VERSION 5.7 ;
BUSBITCHARS "[]" ;
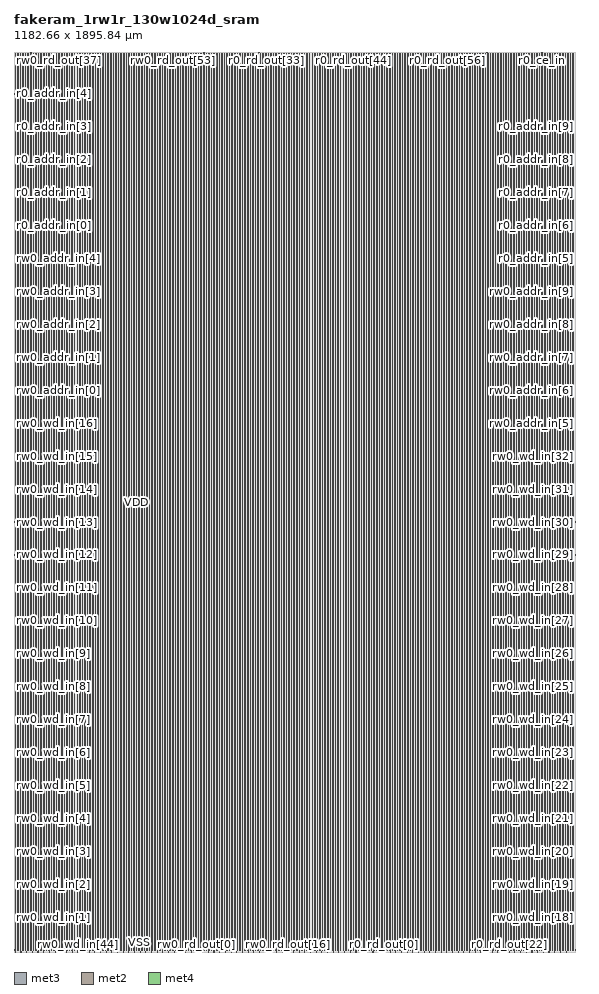
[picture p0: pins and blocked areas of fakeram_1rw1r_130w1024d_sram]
MACRO fakeram_1rw1r_130w1024d_sram
  FOREIGN fakeram_1rw1r_130w1024d_sram 0 0 ;
  SYMMETRY X Y R90 ;
  SIZE 1182.660 BY 1895.840 ;
  CLASS BLOCK ;
  PIN rw0_wd_in[0]
    DIRECTION INPUT ;
    USE SIGNAL ;
    SHAPE ABUTMENT ;
    PORT
      LAYER met3 ;
      RECT 0.000 3.930 0.900 4.230 ;
    END
  END rw0_wd_in[0]
  PIN rw0_wd_in[1]
    DIRECTION INPUT ;
    USE SIGNAL ;
    SHAPE ABUTMENT ;
    PORT
      LAYER met3 ;
      RECT 0.000 73.290 0.900 73.590 ;
    END
  END rw0_wd_in[1]
  PIN rw0_wd_in[2]
    DIRECTION INPUT ;
    USE SIGNAL ;
    SHAPE ABUTMENT ;
    PORT
      LAYER met3 ;
      RECT 0.000 142.650 0.900 142.950 ;
    END
  END rw0_wd_in[2]
  PIN rw0_wd_in[3]
    DIRECTION INPUT ;
    USE SIGNAL ;
    SHAPE ABUTMENT ;
    PORT
      LAYER met3 ;
      RECT 0.000 212.010 0.900 212.310 ;
    END
  END rw0_wd_in[3]
  PIN rw0_wd_in[4]
    DIRECTION INPUT ;
    USE SIGNAL ;
    SHAPE ABUTMENT ;
    PORT
      LAYER met3 ;
      RECT 0.000 281.370 0.900 281.670 ;
    END
  END rw0_wd_in[4]
  PIN rw0_wd_in[5]
    DIRECTION INPUT ;
    USE SIGNAL ;
    SHAPE ABUTMENT ;
    PORT
      LAYER met3 ;
      RECT 0.000 350.730 0.900 351.030 ;
    END
  END rw0_wd_in[5]
  PIN rw0_wd_in[6]
    DIRECTION INPUT ;
    USE SIGNAL ;
    SHAPE ABUTMENT ;
    PORT
      LAYER met3 ;
      RECT 0.000 420.090 0.900 420.390 ;
    END
  END rw0_wd_in[6]
  PIN rw0_wd_in[7]
    DIRECTION INPUT ;
    USE SIGNAL ;
    SHAPE ABUTMENT ;
    PORT
      LAYER met3 ;
      RECT 0.000 489.450 0.900 489.750 ;
    END
  END rw0_wd_in[7]
  PIN rw0_wd_in[8]
    DIRECTION INPUT ;
    USE SIGNAL ;
    SHAPE ABUTMENT ;
    PORT
      LAYER met3 ;
      RECT 0.000 558.810 0.900 559.110 ;
    END
  END rw0_wd_in[8]
  PIN rw0_wd_in[9]
    DIRECTION INPUT ;
    USE SIGNAL ;
    SHAPE ABUTMENT ;
    PORT
      LAYER met3 ;
      RECT 0.000 628.170 0.900 628.470 ;
    END
  END rw0_wd_in[9]
  PIN rw0_wd_in[10]
    DIRECTION INPUT ;
    USE SIGNAL ;
    SHAPE ABUTMENT ;
    PORT
      LAYER met3 ;
      RECT 0.000 697.530 0.900 697.830 ;
    END
  END rw0_wd_in[10]
  PIN rw0_wd_in[11]
    DIRECTION INPUT ;
    USE SIGNAL ;
    SHAPE ABUTMENT ;
    PORT
      LAYER met3 ;
      RECT 0.000 766.890 0.900 767.190 ;
    END
  END rw0_wd_in[11]
  PIN rw0_wd_in[12]
    DIRECTION INPUT ;
    USE SIGNAL ;
    SHAPE ABUTMENT ;
    PORT
      LAYER met3 ;
      RECT 0.000 836.250 0.900 836.550 ;
    END
  END rw0_wd_in[12]
  PIN rw0_wd_in[13]
    DIRECTION INPUT ;
    USE SIGNAL ;
    SHAPE ABUTMENT ;
    PORT
      LAYER met3 ;
      RECT 0.000 905.610 0.900 905.910 ;
    END
  END rw0_wd_in[13]
  PIN rw0_wd_in[14]
    DIRECTION INPUT ;
    USE SIGNAL ;
    SHAPE ABUTMENT ;
    PORT
      LAYER met3 ;
      RECT 0.000 974.970 0.900 975.270 ;
    END
  END rw0_wd_in[14]
  PIN rw0_wd_in[15]
    DIRECTION INPUT ;
    USE SIGNAL ;
    SHAPE ABUTMENT ;
    PORT
      LAYER met3 ;
      RECT 0.000 1044.330 0.900 1044.630 ;
    END
  END rw0_wd_in[15]
  PIN rw0_wd_in[16]
    DIRECTION INPUT ;
    USE SIGNAL ;
    SHAPE ABUTMENT ;
    PORT
      LAYER met3 ;
      RECT 0.000 1113.690 0.900 1113.990 ;
    END
  END rw0_wd_in[16]
  PIN rw0_wd_in[17]
    DIRECTION INPUT ;
    USE SIGNAL ;
    SHAPE ABUTMENT ;
    PORT
      LAYER met3 ;
      RECT 1181.760 3.930 1182.660 4.230 ;
    END
  END rw0_wd_in[17]
  PIN rw0_wd_in[18]
    DIRECTION INPUT ;
    USE SIGNAL ;
    SHAPE ABUTMENT ;
    PORT
      LAYER met3 ;
      RECT 1181.760 73.290 1182.660 73.590 ;
    END
  END rw0_wd_in[18]
  PIN rw0_wd_in[19]
    DIRECTION INPUT ;
    USE SIGNAL ;
    SHAPE ABUTMENT ;
    PORT
      LAYER met3 ;
      RECT 1181.760 142.650 1182.660 142.950 ;
    END
  END rw0_wd_in[19]
  PIN rw0_wd_in[20]
    DIRECTION INPUT ;
    USE SIGNAL ;
    SHAPE ABUTMENT ;
    PORT
      LAYER met3 ;
      RECT 1181.760 212.010 1182.660 212.310 ;
    END
  END rw0_wd_in[20]
  PIN rw0_wd_in[21]
    DIRECTION INPUT ;
    USE SIGNAL ;
    SHAPE ABUTMENT ;
    PORT
      LAYER met3 ;
      RECT 1181.760 281.370 1182.660 281.670 ;
    END
  END rw0_wd_in[21]
  PIN rw0_wd_in[22]
    DIRECTION INPUT ;
    USE SIGNAL ;
    SHAPE ABUTMENT ;
    PORT
      LAYER met3 ;
      RECT 1181.760 350.730 1182.660 351.030 ;
    END
  END rw0_wd_in[22]
  PIN rw0_wd_in[23]
    DIRECTION INPUT ;
    USE SIGNAL ;
    SHAPE ABUTMENT ;
    PORT
      LAYER met3 ;
      RECT 1181.760 420.090 1182.660 420.390 ;
    END
  END rw0_wd_in[23]
  PIN rw0_wd_in[24]
    DIRECTION INPUT ;
    USE SIGNAL ;
    SHAPE ABUTMENT ;
    PORT
      LAYER met3 ;
      RECT 1181.760 489.450 1182.660 489.750 ;
    END
  END rw0_wd_in[24]
  PIN rw0_wd_in[25]
    DIRECTION INPUT ;
    USE SIGNAL ;
    SHAPE ABUTMENT ;
    PORT
      LAYER met3 ;
      RECT 1181.760 558.810 1182.660 559.110 ;
    END
  END rw0_wd_in[25]
  PIN rw0_wd_in[26]
    DIRECTION INPUT ;
    USE SIGNAL ;
    SHAPE ABUTMENT ;
    PORT
      LAYER met3 ;
      RECT 1181.760 628.170 1182.660 628.470 ;
    END
  END rw0_wd_in[26]
  PIN rw0_wd_in[27]
    DIRECTION INPUT ;
    USE SIGNAL ;
    SHAPE ABUTMENT ;
    PORT
      LAYER met3 ;
      RECT 1181.760 697.530 1182.660 697.830 ;
    END
  END rw0_wd_in[27]
  PIN rw0_wd_in[28]
    DIRECTION INPUT ;
    USE SIGNAL ;
    SHAPE ABUTMENT ;
    PORT
      LAYER met3 ;
      RECT 1181.760 766.890 1182.660 767.190 ;
    END
  END rw0_wd_in[28]
  PIN rw0_wd_in[29]
    DIRECTION INPUT ;
    USE SIGNAL ;
    SHAPE ABUTMENT ;
    PORT
      LAYER met3 ;
      RECT 1181.760 836.250 1182.660 836.550 ;
    END
  END rw0_wd_in[29]
  PIN rw0_wd_in[30]
    DIRECTION INPUT ;
    USE SIGNAL ;
    SHAPE ABUTMENT ;
    PORT
      LAYER met3 ;
      RECT 1181.760 905.610 1182.660 905.910 ;
    END
  END rw0_wd_in[30]
  PIN rw0_wd_in[31]
    DIRECTION INPUT ;
    USE SIGNAL ;
    SHAPE ABUTMENT ;
    PORT
      LAYER met3 ;
      RECT 1181.760 974.970 1182.660 975.270 ;
    END
  END rw0_wd_in[31]
  PIN rw0_wd_in[32]
    DIRECTION INPUT ;
    USE SIGNAL ;
    SHAPE ABUTMENT ;
    PORT
      LAYER met3 ;
      RECT 1181.760 1044.330 1182.660 1044.630 ;
    END
  END rw0_wd_in[32]
  PIN rw0_wd_in[33]
    DIRECTION INPUT ;
    USE SIGNAL ;
    SHAPE ABUTMENT ;
    PORT
      LAYER met2 ;
      RECT 2.690 0.000 2.830 0.420 ;
    END
  END rw0_wd_in[33]
  PIN rw0_wd_in[34]
    DIRECTION INPUT ;
    USE SIGNAL ;
    SHAPE ABUTMENT ;
    PORT
      LAYER met2 ;
      RECT 14.650 0.000 14.790 0.420 ;
    END
  END rw0_wd_in[34]
  PIN rw0_wd_in[35]
    DIRECTION INPUT ;
    USE SIGNAL ;
    SHAPE ABUTMENT ;
    PORT
      LAYER met2 ;
      RECT 26.610 0.000 26.750 0.420 ;
    END
  END rw0_wd_in[35]
  PIN rw0_wd_in[36]
    DIRECTION INPUT ;
    USE SIGNAL ;
    SHAPE ABUTMENT ;
    PORT
      LAYER met2 ;
      RECT 38.570 0.000 38.710 0.420 ;
    END
  END rw0_wd_in[36]
  PIN rw0_wd_in[37]
    DIRECTION INPUT ;
    USE SIGNAL ;
    SHAPE ABUTMENT ;
    PORT
      LAYER met2 ;
      RECT 50.530 0.000 50.670 0.420 ;
    END
  END rw0_wd_in[37]
  PIN rw0_wd_in[38]
    DIRECTION INPUT ;
    USE SIGNAL ;
    SHAPE ABUTMENT ;
    PORT
      LAYER met2 ;
      RECT 62.490 0.000 62.630 0.420 ;
    END
  END rw0_wd_in[38]
  PIN rw0_wd_in[39]
    DIRECTION INPUT ;
    USE SIGNAL ;
    SHAPE ABUTMENT ;
    PORT
      LAYER met2 ;
      RECT 74.450 0.000 74.590 0.420 ;
    END
  END rw0_wd_in[39]
  PIN rw0_wd_in[40]
    DIRECTION INPUT ;
    USE SIGNAL ;
    SHAPE ABUTMENT ;
    PORT
      LAYER met2 ;
      RECT 86.410 0.000 86.550 0.420 ;
    END
  END rw0_wd_in[40]
  PIN rw0_wd_in[41]
    DIRECTION INPUT ;
    USE SIGNAL ;
    SHAPE ABUTMENT ;
    PORT
      LAYER met2 ;
      RECT 98.370 0.000 98.510 0.420 ;
    END
  END rw0_wd_in[41]
  PIN rw0_wd_in[42]
    DIRECTION INPUT ;
    USE SIGNAL ;
    SHAPE ABUTMENT ;
    PORT
      LAYER met2 ;
      RECT 110.330 0.000 110.470 0.420 ;
    END
  END rw0_wd_in[42]
  PIN rw0_wd_in[43]
    DIRECTION INPUT ;
    USE SIGNAL ;
    SHAPE ABUTMENT ;
    PORT
      LAYER met2 ;
      RECT 122.290 0.000 122.430 0.420 ;
    END
  END rw0_wd_in[43]
  PIN rw0_wd_in[44]
    DIRECTION INPUT ;
    USE SIGNAL ;
    SHAPE ABUTMENT ;
    PORT
      LAYER met2 ;
      RECT 134.250 0.000 134.390 0.420 ;
    END
  END rw0_wd_in[44]
  PIN rw0_wd_in[45]
    DIRECTION INPUT ;
    USE SIGNAL ;
    SHAPE ABUTMENT ;
    PORT
      LAYER met2 ;
      RECT 146.210 0.000 146.350 0.420 ;
    END
  END rw0_wd_in[45]
  PIN rw0_wd_in[46]
    DIRECTION INPUT ;
    USE SIGNAL ;
    SHAPE ABUTMENT ;
    PORT
      LAYER met2 ;
      RECT 158.170 0.000 158.310 0.420 ;
    END
  END rw0_wd_in[46]
  PIN rw0_wd_in[47]
    DIRECTION INPUT ;
    USE SIGNAL ;
    SHAPE ABUTMENT ;
    PORT
      LAYER met2 ;
      RECT 170.130 0.000 170.270 0.420 ;
    END
  END rw0_wd_in[47]
  PIN rw0_wd_in[48]
    DIRECTION INPUT ;
    USE SIGNAL ;
    SHAPE ABUTMENT ;
    PORT
      LAYER met2 ;
      RECT 182.090 0.000 182.230 0.420 ;
    END
  END rw0_wd_in[48]
  PIN rw0_wd_in[49]
    DIRECTION INPUT ;
    USE SIGNAL ;
    SHAPE ABUTMENT ;
    PORT
      LAYER met2 ;
      RECT 194.050 0.000 194.190 0.420 ;
    END
  END rw0_wd_in[49]
  PIN rw0_wd_in[50]
    DIRECTION INPUT ;
    USE SIGNAL ;
    SHAPE ABUTMENT ;
    PORT
      LAYER met2 ;
      RECT 206.010 0.000 206.150 0.420 ;
    END
  END rw0_wd_in[50]
  PIN rw0_wd_in[51]
    DIRECTION INPUT ;
    USE SIGNAL ;
    SHAPE ABUTMENT ;
    PORT
      LAYER met2 ;
      RECT 217.970 0.000 218.110 0.420 ;
    END
  END rw0_wd_in[51]
  PIN rw0_wd_in[52]
    DIRECTION INPUT ;
    USE SIGNAL ;
    SHAPE ABUTMENT ;
    PORT
      LAYER met2 ;
      RECT 229.930 0.000 230.070 0.420 ;
    END
  END rw0_wd_in[52]
  PIN rw0_wd_in[53]
    DIRECTION INPUT ;
    USE SIGNAL ;
    SHAPE ABUTMENT ;
    PORT
      LAYER met2 ;
      RECT 241.890 0.000 242.030 0.420 ;
    END
  END rw0_wd_in[53]
  PIN rw0_wd_in[54]
    DIRECTION INPUT ;
    USE SIGNAL ;
    SHAPE ABUTMENT ;
    PORT
      LAYER met2 ;
      RECT 253.850 0.000 253.990 0.420 ;
    END
  END rw0_wd_in[54]
  PIN rw0_wd_in[55]
    DIRECTION INPUT ;
    USE SIGNAL ;
    SHAPE ABUTMENT ;
    PORT
      LAYER met2 ;
      RECT 265.810 0.000 265.950 0.420 ;
    END
  END rw0_wd_in[55]
  PIN rw0_wd_in[56]
    DIRECTION INPUT ;
    USE SIGNAL ;
    SHAPE ABUTMENT ;
    PORT
      LAYER met2 ;
      RECT 277.770 0.000 277.910 0.420 ;
    END
  END rw0_wd_in[56]
  PIN rw0_wd_in[57]
    DIRECTION INPUT ;
    USE SIGNAL ;
    SHAPE ABUTMENT ;
    PORT
      LAYER met2 ;
      RECT 289.730 0.000 289.870 0.420 ;
    END
  END rw0_wd_in[57]
  PIN rw0_wd_in[58]
    DIRECTION INPUT ;
    USE SIGNAL ;
    SHAPE ABUTMENT ;
    PORT
      LAYER met2 ;
      RECT 301.690 0.000 301.830 0.420 ;
    END
  END rw0_wd_in[58]
  PIN rw0_wd_in[59]
    DIRECTION INPUT ;
    USE SIGNAL ;
    SHAPE ABUTMENT ;
    PORT
      LAYER met2 ;
      RECT 313.650 0.000 313.790 0.420 ;
    END
  END rw0_wd_in[59]
  PIN rw0_wd_in[60]
    DIRECTION INPUT ;
    USE SIGNAL ;
    SHAPE ABUTMENT ;
    PORT
      LAYER met2 ;
      RECT 325.610 0.000 325.750 0.420 ;
    END
  END rw0_wd_in[60]
  PIN rw0_wd_in[61]
    DIRECTION INPUT ;
    USE SIGNAL ;
    SHAPE ABUTMENT ;
    PORT
      LAYER met2 ;
      RECT 337.570 0.000 337.710 0.420 ;
    END
  END rw0_wd_in[61]
  PIN rw0_wd_in[62]
    DIRECTION INPUT ;
    USE SIGNAL ;
    SHAPE ABUTMENT ;
    PORT
      LAYER met2 ;
      RECT 349.530 0.000 349.670 0.420 ;
    END
  END rw0_wd_in[62]
  PIN rw0_wd_in[63]
    DIRECTION INPUT ;
    USE SIGNAL ;
    SHAPE ABUTMENT ;
    PORT
      LAYER met2 ;
      RECT 361.490 0.000 361.630 0.420 ;
    END
  END rw0_wd_in[63]
  PIN rw0_wd_in[64]
    DIRECTION INPUT ;
    USE SIGNAL ;
    SHAPE ABUTMENT ;
    PORT
      LAYER met2 ;
      RECT 373.450 0.000 373.590 0.420 ;
    END
  END rw0_wd_in[64]
  PIN rw0_rd_out[0]
    DIRECTION OUTPUT ;
    USE SIGNAL ;
    SHAPE ABUTMENT ;
    PORT
      LAYER met2 ;
      RECT 385.410 0.000 385.550 0.420 ;
    END
  END rw0_rd_out[0]
  PIN rw0_rd_out[1]
    DIRECTION OUTPUT ;
    USE SIGNAL ;
    SHAPE ABUTMENT ;
    PORT
      LAYER met2 ;
      RECT 397.370 0.000 397.510 0.420 ;
    END
  END rw0_rd_out[1]
  PIN rw0_rd_out[2]
    DIRECTION OUTPUT ;
    USE SIGNAL ;
    SHAPE ABUTMENT ;
    PORT
      LAYER met2 ;
      RECT 409.330 0.000 409.470 0.420 ;
    END
  END rw0_rd_out[2]
  PIN rw0_rd_out[3]
    DIRECTION OUTPUT ;
    USE SIGNAL ;
    SHAPE ABUTMENT ;
    PORT
      LAYER met2 ;
      RECT 421.290 0.000 421.430 0.420 ;
    END
  END rw0_rd_out[3]
  PIN rw0_rd_out[4]
    DIRECTION OUTPUT ;
    USE SIGNAL ;
    SHAPE ABUTMENT ;
    PORT
      LAYER met2 ;
      RECT 433.250 0.000 433.390 0.420 ;
    END
  END rw0_rd_out[4]
  PIN rw0_rd_out[5]
    DIRECTION OUTPUT ;
    USE SIGNAL ;
    SHAPE ABUTMENT ;
    PORT
      LAYER met2 ;
      RECT 445.210 0.000 445.350 0.420 ;
    END
  END rw0_rd_out[5]
  PIN rw0_rd_out[6]
    DIRECTION OUTPUT ;
    USE SIGNAL ;
    SHAPE ABUTMENT ;
    PORT
      LAYER met2 ;
      RECT 457.170 0.000 457.310 0.420 ;
    END
  END rw0_rd_out[6]
  PIN rw0_rd_out[7]
    DIRECTION OUTPUT ;
    USE SIGNAL ;
    SHAPE ABUTMENT ;
    PORT
      LAYER met2 ;
      RECT 469.130 0.000 469.270 0.420 ;
    END
  END rw0_rd_out[7]
  PIN rw0_rd_out[8]
    DIRECTION OUTPUT ;
    USE SIGNAL ;
    SHAPE ABUTMENT ;
    PORT
      LAYER met2 ;
      RECT 481.090 0.000 481.230 0.420 ;
    END
  END rw0_rd_out[8]
  PIN rw0_rd_out[9]
    DIRECTION OUTPUT ;
    USE SIGNAL ;
    SHAPE ABUTMENT ;
    PORT
      LAYER met2 ;
      RECT 493.050 0.000 493.190 0.420 ;
    END
  END rw0_rd_out[9]
  PIN rw0_rd_out[10]
    DIRECTION OUTPUT ;
    USE SIGNAL ;
    SHAPE ABUTMENT ;
    PORT
      LAYER met2 ;
      RECT 505.010 0.000 505.150 0.420 ;
    END
  END rw0_rd_out[10]
  PIN rw0_rd_out[11]
    DIRECTION OUTPUT ;
    USE SIGNAL ;
    SHAPE ABUTMENT ;
    PORT
      LAYER met2 ;
      RECT 516.970 0.000 517.110 0.420 ;
    END
  END rw0_rd_out[11]
  PIN rw0_rd_out[12]
    DIRECTION OUTPUT ;
    USE SIGNAL ;
    SHAPE ABUTMENT ;
    PORT
      LAYER met2 ;
      RECT 528.930 0.000 529.070 0.420 ;
    END
  END rw0_rd_out[12]
  PIN rw0_rd_out[13]
    DIRECTION OUTPUT ;
    USE SIGNAL ;
    SHAPE ABUTMENT ;
    PORT
      LAYER met2 ;
      RECT 540.890 0.000 541.030 0.420 ;
    END
  END rw0_rd_out[13]
  PIN rw0_rd_out[14]
    DIRECTION OUTPUT ;
    USE SIGNAL ;
    SHAPE ABUTMENT ;
    PORT
      LAYER met2 ;
      RECT 552.850 0.000 552.990 0.420 ;
    END
  END rw0_rd_out[14]
  PIN rw0_rd_out[15]
    DIRECTION OUTPUT ;
    USE SIGNAL ;
    SHAPE ABUTMENT ;
    PORT
      LAYER met2 ;
      RECT 564.810 0.000 564.950 0.420 ;
    END
  END rw0_rd_out[15]
  PIN rw0_rd_out[16]
    DIRECTION OUTPUT ;
    USE SIGNAL ;
    SHAPE ABUTMENT ;
    PORT
      LAYER met2 ;
      RECT 576.770 0.000 576.910 0.420 ;
    END
  END rw0_rd_out[16]
  PIN rw0_rd_out[17]
    DIRECTION OUTPUT ;
    USE SIGNAL ;
    SHAPE ABUTMENT ;
    PORT
      LAYER met2 ;
      RECT 588.730 0.000 588.870 0.420 ;
    END
  END rw0_rd_out[17]
  PIN rw0_rd_out[18]
    DIRECTION OUTPUT ;
    USE SIGNAL ;
    SHAPE ABUTMENT ;
    PORT
      LAYER met2 ;
      RECT 600.690 0.000 600.830 0.420 ;
    END
  END rw0_rd_out[18]
  PIN rw0_rd_out[19]
    DIRECTION OUTPUT ;
    USE SIGNAL ;
    SHAPE ABUTMENT ;
    PORT
      LAYER met2 ;
      RECT 612.650 0.000 612.790 0.420 ;
    END
  END rw0_rd_out[19]
  PIN rw0_rd_out[20]
    DIRECTION OUTPUT ;
    USE SIGNAL ;
    SHAPE ABUTMENT ;
    PORT
      LAYER met2 ;
      RECT 624.610 0.000 624.750 0.420 ;
    END
  END rw0_rd_out[20]
  PIN rw0_rd_out[21]
    DIRECTION OUTPUT ;
    USE SIGNAL ;
    SHAPE ABUTMENT ;
    PORT
      LAYER met2 ;
      RECT 636.570 0.000 636.710 0.420 ;
    END
  END rw0_rd_out[21]
  PIN rw0_rd_out[22]
    DIRECTION OUTPUT ;
    USE SIGNAL ;
    SHAPE ABUTMENT ;
    PORT
      LAYER met2 ;
      RECT 648.530 0.000 648.670 0.420 ;
    END
  END rw0_rd_out[22]
  PIN rw0_rd_out[23]
    DIRECTION OUTPUT ;
    USE SIGNAL ;
    SHAPE ABUTMENT ;
    PORT
      LAYER met2 ;
      RECT 660.490 0.000 660.630 0.420 ;
    END
  END rw0_rd_out[23]
  PIN rw0_rd_out[24]
    DIRECTION OUTPUT ;
    USE SIGNAL ;
    SHAPE ABUTMENT ;
    PORT
      LAYER met2 ;
      RECT 672.450 0.000 672.590 0.420 ;
    END
  END rw0_rd_out[24]
  PIN rw0_rd_out[25]
    DIRECTION OUTPUT ;
    USE SIGNAL ;
    SHAPE ABUTMENT ;
    PORT
      LAYER met2 ;
      RECT 684.410 0.000 684.550 0.420 ;
    END
  END rw0_rd_out[25]
  PIN rw0_rd_out[26]
    DIRECTION OUTPUT ;
    USE SIGNAL ;
    SHAPE ABUTMENT ;
    PORT
      LAYER met2 ;
      RECT 696.370 0.000 696.510 0.420 ;
    END
  END rw0_rd_out[26]
  PIN rw0_rd_out[27]
    DIRECTION OUTPUT ;
    USE SIGNAL ;
    SHAPE ABUTMENT ;
    PORT
      LAYER met2 ;
      RECT 708.330 0.000 708.470 0.420 ;
    END
  END rw0_rd_out[27]
  PIN rw0_rd_out[28]
    DIRECTION OUTPUT ;
    USE SIGNAL ;
    SHAPE ABUTMENT ;
    PORT
      LAYER met2 ;
      RECT 720.290 0.000 720.430 0.420 ;
    END
  END rw0_rd_out[28]
  PIN rw0_rd_out[29]
    DIRECTION OUTPUT ;
    USE SIGNAL ;
    SHAPE ABUTMENT ;
    PORT
      LAYER met2 ;
      RECT 732.250 0.000 732.390 0.420 ;
    END
  END rw0_rd_out[29]
  PIN rw0_rd_out[30]
    DIRECTION OUTPUT ;
    USE SIGNAL ;
    SHAPE ABUTMENT ;
    PORT
      LAYER met2 ;
      RECT 744.210 0.000 744.350 0.420 ;
    END
  END rw0_rd_out[30]
  PIN rw0_rd_out[31]
    DIRECTION OUTPUT ;
    USE SIGNAL ;
    SHAPE ABUTMENT ;
    PORT
      LAYER met2 ;
      RECT 756.170 0.000 756.310 0.420 ;
    END
  END rw0_rd_out[31]
  PIN rw0_rd_out[32]
    DIRECTION OUTPUT ;
    USE SIGNAL ;
    SHAPE ABUTMENT ;
    PORT
      LAYER met2 ;
      RECT 768.130 0.000 768.270 0.420 ;
    END
  END rw0_rd_out[32]
  PIN rw0_rd_out[33]
    DIRECTION OUTPUT ;
    USE SIGNAL ;
    SHAPE ABUTMENT ;
    PORT
      LAYER met2 ;
      RECT 2.690 1895.420 2.830 1895.840 ;
    END
  END rw0_rd_out[33]
  PIN rw0_rd_out[34]
    DIRECTION OUTPUT ;
    USE SIGNAL ;
    SHAPE ABUTMENT ;
    PORT
      LAYER met2 ;
      RECT 19.250 1895.420 19.390 1895.840 ;
    END
  END rw0_rd_out[34]
  PIN rw0_rd_out[35]
    DIRECTION OUTPUT ;
    USE SIGNAL ;
    SHAPE ABUTMENT ;
    PORT
      LAYER met2 ;
      RECT 35.810 1895.420 35.950 1895.840 ;
    END
  END rw0_rd_out[35]
  PIN rw0_rd_out[36]
    DIRECTION OUTPUT ;
    USE SIGNAL ;
    SHAPE ABUTMENT ;
    PORT
      LAYER met2 ;
      RECT 52.370 1895.420 52.510 1895.840 ;
    END
  END rw0_rd_out[36]
  PIN rw0_rd_out[37]
    DIRECTION OUTPUT ;
    USE SIGNAL ;
    SHAPE ABUTMENT ;
    PORT
      LAYER met2 ;
      RECT 68.930 1895.420 69.070 1895.840 ;
    END
  END rw0_rd_out[37]
  PIN rw0_rd_out[38]
    DIRECTION OUTPUT ;
    USE SIGNAL ;
    SHAPE ABUTMENT ;
    PORT
      LAYER met2 ;
      RECT 85.490 1895.420 85.630 1895.840 ;
    END
  END rw0_rd_out[38]
  PIN rw0_rd_out[39]
    DIRECTION OUTPUT ;
    USE SIGNAL ;
    SHAPE ABUTMENT ;
    PORT
      LAYER met2 ;
      RECT 102.050 1895.420 102.190 1895.840 ;
    END
  END rw0_rd_out[39]
  PIN rw0_rd_out[40]
    DIRECTION OUTPUT ;
    USE SIGNAL ;
    SHAPE ABUTMENT ;
    PORT
      LAYER met2 ;
      RECT 118.610 1895.420 118.750 1895.840 ;
    END
  END rw0_rd_out[40]
  PIN rw0_rd_out[41]
    DIRECTION OUTPUT ;
    USE SIGNAL ;
    SHAPE ABUTMENT ;
    PORT
      LAYER met2 ;
      RECT 135.170 1895.420 135.310 1895.840 ;
    END
  END rw0_rd_out[41]
  PIN rw0_rd_out[42]
    DIRECTION OUTPUT ;
    USE SIGNAL ;
    SHAPE ABUTMENT ;
    PORT
      LAYER met2 ;
      RECT 151.730 1895.420 151.870 1895.840 ;
    END
  END rw0_rd_out[42]
  PIN rw0_rd_out[43]
    DIRECTION OUTPUT ;
    USE SIGNAL ;
    SHAPE ABUTMENT ;
    PORT
      LAYER met2 ;
      RECT 168.290 1895.420 168.430 1895.840 ;
    END
  END rw0_rd_out[43]
  PIN rw0_rd_out[44]
    DIRECTION OUTPUT ;
    USE SIGNAL ;
    SHAPE ABUTMENT ;
    PORT
      LAYER met2 ;
      RECT 184.850 1895.420 184.990 1895.840 ;
    END
  END rw0_rd_out[44]
  PIN rw0_rd_out[45]
    DIRECTION OUTPUT ;
    USE SIGNAL ;
    SHAPE ABUTMENT ;
    PORT
      LAYER met2 ;
      RECT 201.410 1895.420 201.550 1895.840 ;
    END
  END rw0_rd_out[45]
  PIN rw0_rd_out[46]
    DIRECTION OUTPUT ;
    USE SIGNAL ;
    SHAPE ABUTMENT ;
    PORT
      LAYER met2 ;
      RECT 217.970 1895.420 218.110 1895.840 ;
    END
  END rw0_rd_out[46]
  PIN rw0_rd_out[47]
    DIRECTION OUTPUT ;
    USE SIGNAL ;
    SHAPE ABUTMENT ;
    PORT
      LAYER met2 ;
      RECT 234.530 1895.420 234.670 1895.840 ;
    END
  END rw0_rd_out[47]
  PIN rw0_rd_out[48]
    DIRECTION OUTPUT ;
    USE SIGNAL ;
    SHAPE ABUTMENT ;
    PORT
      LAYER met2 ;
      RECT 251.090 1895.420 251.230 1895.840 ;
    END
  END rw0_rd_out[48]
  PIN rw0_rd_out[49]
    DIRECTION OUTPUT ;
    USE SIGNAL ;
    SHAPE ABUTMENT ;
    PORT
      LAYER met2 ;
      RECT 267.650 1895.420 267.790 1895.840 ;
    END
  END rw0_rd_out[49]
  PIN rw0_rd_out[50]
    DIRECTION OUTPUT ;
    USE SIGNAL ;
    SHAPE ABUTMENT ;
    PORT
      LAYER met2 ;
      RECT 284.210 1895.420 284.350 1895.840 ;
    END
  END rw0_rd_out[50]
  PIN rw0_rd_out[51]
    DIRECTION OUTPUT ;
    USE SIGNAL ;
    SHAPE ABUTMENT ;
    PORT
      LAYER met2 ;
      RECT 300.770 1895.420 300.910 1895.840 ;
    END
  END rw0_rd_out[51]
  PIN rw0_rd_out[52]
    DIRECTION OUTPUT ;
    USE SIGNAL ;
    SHAPE ABUTMENT ;
    PORT
      LAYER met2 ;
      RECT 317.330 1895.420 317.470 1895.840 ;
    END
  END rw0_rd_out[52]
  PIN rw0_rd_out[53]
    DIRECTION OUTPUT ;
    USE SIGNAL ;
    SHAPE ABUTMENT ;
    PORT
      LAYER met2 ;
      RECT 333.890 1895.420 334.030 1895.840 ;
    END
  END rw0_rd_out[53]
  PIN rw0_rd_out[54]
    DIRECTION OUTPUT ;
    USE SIGNAL ;
    SHAPE ABUTMENT ;
    PORT
      LAYER met2 ;
      RECT 350.450 1895.420 350.590 1895.840 ;
    END
  END rw0_rd_out[54]
  PIN rw0_rd_out[55]
    DIRECTION OUTPUT ;
    USE SIGNAL ;
    SHAPE ABUTMENT ;
    PORT
      LAYER met2 ;
      RECT 367.010 1895.420 367.150 1895.840 ;
    END
  END rw0_rd_out[55]
  PIN rw0_rd_out[56]
    DIRECTION OUTPUT ;
    USE SIGNAL ;
    SHAPE ABUTMENT ;
    PORT
      LAYER met2 ;
      RECT 383.570 1895.420 383.710 1895.840 ;
    END
  END rw0_rd_out[56]
  PIN rw0_rd_out[57]
    DIRECTION OUTPUT ;
    USE SIGNAL ;
    SHAPE ABUTMENT ;
    PORT
      LAYER met2 ;
      RECT 400.130 1895.420 400.270 1895.840 ;
    END
  END rw0_rd_out[57]
  PIN rw0_rd_out[58]
    DIRECTION OUTPUT ;
    USE SIGNAL ;
    SHAPE ABUTMENT ;
    PORT
      LAYER met2 ;
      RECT 416.690 1895.420 416.830 1895.840 ;
    END
  END rw0_rd_out[58]
  PIN rw0_rd_out[59]
    DIRECTION OUTPUT ;
    USE SIGNAL ;
    SHAPE ABUTMENT ;
    PORT
      LAYER met2 ;
      RECT 433.250 1895.420 433.390 1895.840 ;
    END
  END rw0_rd_out[59]
  PIN rw0_rd_out[60]
    DIRECTION OUTPUT ;
    USE SIGNAL ;
    SHAPE ABUTMENT ;
    PORT
      LAYER met2 ;
      RECT 449.810 1895.420 449.950 1895.840 ;
    END
  END rw0_rd_out[60]
  PIN rw0_rd_out[61]
    DIRECTION OUTPUT ;
    USE SIGNAL ;
    SHAPE ABUTMENT ;
    PORT
      LAYER met2 ;
      RECT 466.370 1895.420 466.510 1895.840 ;
    END
  END rw0_rd_out[61]
  PIN rw0_rd_out[62]
    DIRECTION OUTPUT ;
    USE SIGNAL ;
    SHAPE ABUTMENT ;
    PORT
      LAYER met2 ;
      RECT 482.930 1895.420 483.070 1895.840 ;
    END
  END rw0_rd_out[62]
  PIN rw0_rd_out[63]
    DIRECTION OUTPUT ;
    USE SIGNAL ;
    SHAPE ABUTMENT ;
    PORT
      LAYER met2 ;
      RECT 499.490 1895.420 499.630 1895.840 ;
    END
  END rw0_rd_out[63]
  PIN rw0_rd_out[64]
    DIRECTION OUTPUT ;
    USE SIGNAL ;
    SHAPE ABUTMENT ;
    PORT
      LAYER met2 ;
      RECT 516.050 1895.420 516.190 1895.840 ;
    END
  END rw0_rd_out[64]
  PIN r0_rd_out[0]
    DIRECTION OUTPUT ;
    USE SIGNAL ;
    SHAPE ABUTMENT ;
    PORT
      LAYER met2 ;
      RECT 780.090 0.000 780.230 0.420 ;
    END
  END r0_rd_out[0]
  PIN r0_rd_out[1]
    DIRECTION OUTPUT ;
    USE SIGNAL ;
    SHAPE ABUTMENT ;
    PORT
      LAYER met2 ;
      RECT 792.050 0.000 792.190 0.420 ;
    END
  END r0_rd_out[1]
  PIN r0_rd_out[2]
    DIRECTION OUTPUT ;
    USE SIGNAL ;
    SHAPE ABUTMENT ;
    PORT
      LAYER met2 ;
      RECT 804.010 0.000 804.150 0.420 ;
    END
  END r0_rd_out[2]
  PIN r0_rd_out[3]
    DIRECTION OUTPUT ;
    USE SIGNAL ;
    SHAPE ABUTMENT ;
    PORT
      LAYER met2 ;
      RECT 815.970 0.000 816.110 0.420 ;
    END
  END r0_rd_out[3]
  PIN r0_rd_out[4]
    DIRECTION OUTPUT ;
    USE SIGNAL ;
    SHAPE ABUTMENT ;
    PORT
      LAYER met2 ;
      RECT 827.930 0.000 828.070 0.420 ;
    END
  END r0_rd_out[4]
  PIN r0_rd_out[5]
    DIRECTION OUTPUT ;
    USE SIGNAL ;
    SHAPE ABUTMENT ;
    PORT
      LAYER met2 ;
      RECT 839.890 0.000 840.030 0.420 ;
    END
  END r0_rd_out[5]
  PIN r0_rd_out[6]
    DIRECTION OUTPUT ;
    USE SIGNAL ;
    SHAPE ABUTMENT ;
    PORT
      LAYER met2 ;
      RECT 851.850 0.000 851.990 0.420 ;
    END
  END r0_rd_out[6]
  PIN r0_rd_out[7]
    DIRECTION OUTPUT ;
    USE SIGNAL ;
    SHAPE ABUTMENT ;
    PORT
      LAYER met2 ;
      RECT 863.810 0.000 863.950 0.420 ;
    END
  END r0_rd_out[7]
  PIN r0_rd_out[8]
    DIRECTION OUTPUT ;
    USE SIGNAL ;
    SHAPE ABUTMENT ;
    PORT
      LAYER met2 ;
      RECT 875.770 0.000 875.910 0.420 ;
    END
  END r0_rd_out[8]
  PIN r0_rd_out[9]
    DIRECTION OUTPUT ;
    USE SIGNAL ;
    SHAPE ABUTMENT ;
    PORT
      LAYER met2 ;
      RECT 887.730 0.000 887.870 0.420 ;
    END
  END r0_rd_out[9]
  PIN r0_rd_out[10]
    DIRECTION OUTPUT ;
    USE SIGNAL ;
    SHAPE ABUTMENT ;
    PORT
      LAYER met2 ;
      RECT 899.690 0.000 899.830 0.420 ;
    END
  END r0_rd_out[10]
  PIN r0_rd_out[11]
    DIRECTION OUTPUT ;
    USE SIGNAL ;
    SHAPE ABUTMENT ;
    PORT
      LAYER met2 ;
      RECT 911.650 0.000 911.790 0.420 ;
    END
  END r0_rd_out[11]
  PIN r0_rd_out[12]
    DIRECTION OUTPUT ;
    USE SIGNAL ;
    SHAPE ABUTMENT ;
    PORT
      LAYER met2 ;
      RECT 923.610 0.000 923.750 0.420 ;
    END
  END r0_rd_out[12]
  PIN r0_rd_out[13]
    DIRECTION OUTPUT ;
    USE SIGNAL ;
    SHAPE ABUTMENT ;
    PORT
      LAYER met2 ;
      RECT 935.570 0.000 935.710 0.420 ;
    END
  END r0_rd_out[13]
  PIN r0_rd_out[14]
    DIRECTION OUTPUT ;
    USE SIGNAL ;
    SHAPE ABUTMENT ;
    PORT
      LAYER met2 ;
      RECT 947.530 0.000 947.670 0.420 ;
    END
  END r0_rd_out[14]
  PIN r0_rd_out[15]
    DIRECTION OUTPUT ;
    USE SIGNAL ;
    SHAPE ABUTMENT ;
    PORT
      LAYER met2 ;
      RECT 959.490 0.000 959.630 0.420 ;
    END
  END r0_rd_out[15]
  PIN r0_rd_out[16]
    DIRECTION OUTPUT ;
    USE SIGNAL ;
    SHAPE ABUTMENT ;
    PORT
      LAYER met2 ;
      RECT 971.450 0.000 971.590 0.420 ;
    END
  END r0_rd_out[16]
  PIN r0_rd_out[17]
    DIRECTION OUTPUT ;
    USE SIGNAL ;
    SHAPE ABUTMENT ;
    PORT
      LAYER met2 ;
      RECT 983.410 0.000 983.550 0.420 ;
    END
  END r0_rd_out[17]
  PIN r0_rd_out[18]
    DIRECTION OUTPUT ;
    USE SIGNAL ;
    SHAPE ABUTMENT ;
    PORT
      LAYER met2 ;
      RECT 995.370 0.000 995.510 0.420 ;
    END
  END r0_rd_out[18]
  PIN r0_rd_out[19]
    DIRECTION OUTPUT ;
    USE SIGNAL ;
    SHAPE ABUTMENT ;
    PORT
      LAYER met2 ;
      RECT 1007.330 0.000 1007.470 0.420 ;
    END
  END r0_rd_out[19]
  PIN r0_rd_out[20]
    DIRECTION OUTPUT ;
    USE SIGNAL ;
    SHAPE ABUTMENT ;
    PORT
      LAYER met2 ;
      RECT 1019.290 0.000 1019.430 0.420 ;
    END
  END r0_rd_out[20]
  PIN r0_rd_out[21]
    DIRECTION OUTPUT ;
    USE SIGNAL ;
    SHAPE ABUTMENT ;
    PORT
      LAYER met2 ;
      RECT 1031.250 0.000 1031.390 0.420 ;
    END
  END r0_rd_out[21]
  PIN r0_rd_out[22]
    DIRECTION OUTPUT ;
    USE SIGNAL ;
    SHAPE ABUTMENT ;
    PORT
      LAYER met2 ;
      RECT 1043.210 0.000 1043.350 0.420 ;
    END
  END r0_rd_out[22]
  PIN r0_rd_out[23]
    DIRECTION OUTPUT ;
    USE SIGNAL ;
    SHAPE ABUTMENT ;
    PORT
      LAYER met2 ;
      RECT 1055.170 0.000 1055.310 0.420 ;
    END
  END r0_rd_out[23]
  PIN r0_rd_out[24]
    DIRECTION OUTPUT ;
    USE SIGNAL ;
    SHAPE ABUTMENT ;
    PORT
      LAYER met2 ;
      RECT 1067.130 0.000 1067.270 0.420 ;
    END
  END r0_rd_out[24]
  PIN r0_rd_out[25]
    DIRECTION OUTPUT ;
    USE SIGNAL ;
    SHAPE ABUTMENT ;
    PORT
      LAYER met2 ;
      RECT 1079.090 0.000 1079.230 0.420 ;
    END
  END r0_rd_out[25]
  PIN r0_rd_out[26]
    DIRECTION OUTPUT ;
    USE SIGNAL ;
    SHAPE ABUTMENT ;
    PORT
      LAYER met2 ;
      RECT 1091.050 0.000 1091.190 0.420 ;
    END
  END r0_rd_out[26]
  PIN r0_rd_out[27]
    DIRECTION OUTPUT ;
    USE SIGNAL ;
    SHAPE ABUTMENT ;
    PORT
      LAYER met2 ;
      RECT 1103.010 0.000 1103.150 0.420 ;
    END
  END r0_rd_out[27]
  PIN r0_rd_out[28]
    DIRECTION OUTPUT ;
    USE SIGNAL ;
    SHAPE ABUTMENT ;
    PORT
      LAYER met2 ;
      RECT 1114.970 0.000 1115.110 0.420 ;
    END
  END r0_rd_out[28]
  PIN r0_rd_out[29]
    DIRECTION OUTPUT ;
    USE SIGNAL ;
    SHAPE ABUTMENT ;
    PORT
      LAYER met2 ;
      RECT 1126.930 0.000 1127.070 0.420 ;
    END
  END r0_rd_out[29]
  PIN r0_rd_out[30]
    DIRECTION OUTPUT ;
    USE SIGNAL ;
    SHAPE ABUTMENT ;
    PORT
      LAYER met2 ;
      RECT 1138.890 0.000 1139.030 0.420 ;
    END
  END r0_rd_out[30]
  PIN r0_rd_out[31]
    DIRECTION OUTPUT ;
    USE SIGNAL ;
    SHAPE ABUTMENT ;
    PORT
      LAYER met2 ;
      RECT 1150.850 0.000 1150.990 0.420 ;
    END
  END r0_rd_out[31]
  PIN r0_rd_out[32]
    DIRECTION OUTPUT ;
    USE SIGNAL ;
    SHAPE ABUTMENT ;
    PORT
      LAYER met2 ;
      RECT 1162.810 0.000 1162.950 0.420 ;
    END
  END r0_rd_out[32]
  PIN r0_rd_out[33]
    DIRECTION OUTPUT ;
    USE SIGNAL ;
    SHAPE ABUTMENT ;
    PORT
      LAYER met2 ;
      RECT 532.610 1895.420 532.750 1895.840 ;
    END
  END r0_rd_out[33]
  PIN r0_rd_out[34]
    DIRECTION OUTPUT ;
    USE SIGNAL ;
    SHAPE ABUTMENT ;
    PORT
      LAYER met2 ;
      RECT 549.170 1895.420 549.310 1895.840 ;
    END
  END r0_rd_out[34]
  PIN r0_rd_out[35]
    DIRECTION OUTPUT ;
    USE SIGNAL ;
    SHAPE ABUTMENT ;
    PORT
      LAYER met2 ;
      RECT 565.730 1895.420 565.870 1895.840 ;
    END
  END r0_rd_out[35]
  PIN r0_rd_out[36]
    DIRECTION OUTPUT ;
    USE SIGNAL ;
    SHAPE ABUTMENT ;
    PORT
      LAYER met2 ;
      RECT 582.290 1895.420 582.430 1895.840 ;
    END
  END r0_rd_out[36]
  PIN r0_rd_out[37]
    DIRECTION OUTPUT ;
    USE SIGNAL ;
    SHAPE ABUTMENT ;
    PORT
      LAYER met2 ;
      RECT 598.850 1895.420 598.990 1895.840 ;
    END
  END r0_rd_out[37]
  PIN r0_rd_out[38]
    DIRECTION OUTPUT ;
    USE SIGNAL ;
    SHAPE ABUTMENT ;
    PORT
      LAYER met2 ;
      RECT 615.410 1895.420 615.550 1895.840 ;
    END
  END r0_rd_out[38]
  PIN r0_rd_out[39]
    DIRECTION OUTPUT ;
    USE SIGNAL ;
    SHAPE ABUTMENT ;
    PORT
      LAYER met2 ;
      RECT 631.970 1895.420 632.110 1895.840 ;
    END
  END r0_rd_out[39]
  PIN r0_rd_out[40]
    DIRECTION OUTPUT ;
    USE SIGNAL ;
    SHAPE ABUTMENT ;
    PORT
      LAYER met2 ;
      RECT 648.530 1895.420 648.670 1895.840 ;
    END
  END r0_rd_out[40]
  PIN r0_rd_out[41]
    DIRECTION OUTPUT ;
    USE SIGNAL ;
    SHAPE ABUTMENT ;
    PORT
      LAYER met2 ;
      RECT 665.090 1895.420 665.230 1895.840 ;
    END
  END r0_rd_out[41]
  PIN r0_rd_out[42]
    DIRECTION OUTPUT ;
    USE SIGNAL ;
    SHAPE ABUTMENT ;
    PORT
      LAYER met2 ;
      RECT 681.650 1895.420 681.790 1895.840 ;
    END
  END r0_rd_out[42]
  PIN r0_rd_out[43]
    DIRECTION OUTPUT ;
    USE SIGNAL ;
    SHAPE ABUTMENT ;
    PORT
      LAYER met2 ;
      RECT 698.210 1895.420 698.350 1895.840 ;
    END
  END r0_rd_out[43]
  PIN r0_rd_out[44]
    DIRECTION OUTPUT ;
    USE SIGNAL ;
    SHAPE ABUTMENT ;
    PORT
      LAYER met2 ;
      RECT 714.770 1895.420 714.910 1895.840 ;
    END
  END r0_rd_out[44]
  PIN r0_rd_out[45]
    DIRECTION OUTPUT ;
    USE SIGNAL ;
    SHAPE ABUTMENT ;
    PORT
      LAYER met2 ;
      RECT 731.330 1895.420 731.470 1895.840 ;
    END
  END r0_rd_out[45]
  PIN r0_rd_out[46]
    DIRECTION OUTPUT ;
    USE SIGNAL ;
    SHAPE ABUTMENT ;
    PORT
      LAYER met2 ;
      RECT 747.890 1895.420 748.030 1895.840 ;
    END
  END r0_rd_out[46]
  PIN r0_rd_out[47]
    DIRECTION OUTPUT ;
    USE SIGNAL ;
    SHAPE ABUTMENT ;
    PORT
      LAYER met2 ;
      RECT 764.450 1895.420 764.590 1895.840 ;
    END
  END r0_rd_out[47]
  PIN r0_rd_out[48]
    DIRECTION OUTPUT ;
    USE SIGNAL ;
    SHAPE ABUTMENT ;
    PORT
      LAYER met2 ;
      RECT 781.010 1895.420 781.150 1895.840 ;
    END
  END r0_rd_out[48]
  PIN r0_rd_out[49]
    DIRECTION OUTPUT ;
    USE SIGNAL ;
    SHAPE ABUTMENT ;
    PORT
      LAYER met2 ;
      RECT 797.570 1895.420 797.710 1895.840 ;
    END
  END r0_rd_out[49]
  PIN r0_rd_out[50]
    DIRECTION OUTPUT ;
    USE SIGNAL ;
    SHAPE ABUTMENT ;
    PORT
      LAYER met2 ;
      RECT 814.130 1895.420 814.270 1895.840 ;
    END
  END r0_rd_out[50]
  PIN r0_rd_out[51]
    DIRECTION OUTPUT ;
    USE SIGNAL ;
    SHAPE ABUTMENT ;
    PORT
      LAYER met2 ;
      RECT 830.690 1895.420 830.830 1895.840 ;
    END
  END r0_rd_out[51]
  PIN r0_rd_out[52]
    DIRECTION OUTPUT ;
    USE SIGNAL ;
    SHAPE ABUTMENT ;
    PORT
      LAYER met2 ;
      RECT 847.250 1895.420 847.390 1895.840 ;
    END
  END r0_rd_out[52]
  PIN r0_rd_out[53]
    DIRECTION OUTPUT ;
    USE SIGNAL ;
    SHAPE ABUTMENT ;
    PORT
      LAYER met2 ;
      RECT 863.810 1895.420 863.950 1895.840 ;
    END
  END r0_rd_out[53]
  PIN r0_rd_out[54]
    DIRECTION OUTPUT ;
    USE SIGNAL ;
    SHAPE ABUTMENT ;
    PORT
      LAYER met2 ;
      RECT 880.370 1895.420 880.510 1895.840 ;
    END
  END r0_rd_out[54]
  PIN r0_rd_out[55]
    DIRECTION OUTPUT ;
    USE SIGNAL ;
    SHAPE ABUTMENT ;
    PORT
      LAYER met2 ;
      RECT 896.930 1895.420 897.070 1895.840 ;
    END
  END r0_rd_out[55]
  PIN r0_rd_out[56]
    DIRECTION OUTPUT ;
    USE SIGNAL ;
    SHAPE ABUTMENT ;
    PORT
      LAYER met2 ;
      RECT 913.490 1895.420 913.630 1895.840 ;
    END
  END r0_rd_out[56]
  PIN r0_rd_out[57]
    DIRECTION OUTPUT ;
    USE SIGNAL ;
    SHAPE ABUTMENT ;
    PORT
      LAYER met2 ;
      RECT 930.050 1895.420 930.190 1895.840 ;
    END
  END r0_rd_out[57]
  PIN r0_rd_out[58]
    DIRECTION OUTPUT ;
    USE SIGNAL ;
    SHAPE ABUTMENT ;
    PORT
      LAYER met2 ;
      RECT 946.610 1895.420 946.750 1895.840 ;
    END
  END r0_rd_out[58]
  PIN r0_rd_out[59]
    DIRECTION OUTPUT ;
    USE SIGNAL ;
    SHAPE ABUTMENT ;
    PORT
      LAYER met2 ;
      RECT 963.170 1895.420 963.310 1895.840 ;
    END
  END r0_rd_out[59]
  PIN r0_rd_out[60]
    DIRECTION OUTPUT ;
    USE SIGNAL ;
    SHAPE ABUTMENT ;
    PORT
      LAYER met2 ;
      RECT 979.730 1895.420 979.870 1895.840 ;
    END
  END r0_rd_out[60]
  PIN r0_rd_out[61]
    DIRECTION OUTPUT ;
    USE SIGNAL ;
    SHAPE ABUTMENT ;
    PORT
      LAYER met2 ;
      RECT 996.290 1895.420 996.430 1895.840 ;
    END
  END r0_rd_out[61]
  PIN r0_rd_out[62]
    DIRECTION OUTPUT ;
    USE SIGNAL ;
    SHAPE ABUTMENT ;
    PORT
      LAYER met2 ;
      RECT 1012.850 1895.420 1012.990 1895.840 ;
    END
  END r0_rd_out[62]
  PIN r0_rd_out[63]
    DIRECTION OUTPUT ;
    USE SIGNAL ;
    SHAPE ABUTMENT ;
    PORT
      LAYER met2 ;
      RECT 1029.410 1895.420 1029.550 1895.840 ;
    END
  END r0_rd_out[63]
  PIN r0_rd_out[64]
    DIRECTION OUTPUT ;
    USE SIGNAL ;
    SHAPE ABUTMENT ;
    PORT
      LAYER met2 ;
      RECT 1045.970 1895.420 1046.110 1895.840 ;
    END
  END r0_rd_out[64]
  PIN rw0_addr_in[0]
    DIRECTION INPUT ;
    USE SIGNAL ;
    SHAPE ABUTMENT ;
    PORT
      LAYER met3 ;
      RECT 0.000 1183.050 0.900 1183.350 ;
    END
  END rw0_addr_in[0]
  PIN rw0_addr_in[1]
    DIRECTION INPUT ;
    USE SIGNAL ;
    SHAPE ABUTMENT ;
    PORT
      LAYER met3 ;
      RECT 0.000 1252.410 0.900 1252.710 ;
    END
  END rw0_addr_in[1]
  PIN rw0_addr_in[2]
    DIRECTION INPUT ;
    USE SIGNAL ;
    SHAPE ABUTMENT ;
    PORT
      LAYER met3 ;
      RECT 0.000 1321.770 0.900 1322.070 ;
    END
  END rw0_addr_in[2]
  PIN rw0_addr_in[3]
    DIRECTION INPUT ;
    USE SIGNAL ;
    SHAPE ABUTMENT ;
    PORT
      LAYER met3 ;
      RECT 0.000 1391.130 0.900 1391.430 ;
    END
  END rw0_addr_in[3]
  PIN rw0_addr_in[4]
    DIRECTION INPUT ;
    USE SIGNAL ;
    SHAPE ABUTMENT ;
    PORT
      LAYER met3 ;
      RECT 0.000 1460.490 0.900 1460.790 ;
    END
  END rw0_addr_in[4]
  PIN rw0_addr_in[5]
    DIRECTION INPUT ;
    USE SIGNAL ;
    SHAPE ABUTMENT ;
    PORT
      LAYER met3 ;
      RECT 1181.760 1113.690 1182.660 1113.990 ;
    END
  END rw0_addr_in[5]
  PIN rw0_addr_in[6]
    DIRECTION INPUT ;
    USE SIGNAL ;
    SHAPE ABUTMENT ;
    PORT
      LAYER met3 ;
      RECT 1181.760 1183.050 1182.660 1183.350 ;
    END
  END rw0_addr_in[6]
  PIN rw0_addr_in[7]
    DIRECTION INPUT ;
    USE SIGNAL ;
    SHAPE ABUTMENT ;
    PORT
      LAYER met3 ;
      RECT 1181.760 1252.410 1182.660 1252.710 ;
    END
  END rw0_addr_in[7]
  PIN rw0_addr_in[8]
    DIRECTION INPUT ;
    USE SIGNAL ;
    SHAPE ABUTMENT ;
    PORT
      LAYER met3 ;
      RECT 1181.760 1321.770 1182.660 1322.070 ;
    END
  END rw0_addr_in[8]
  PIN rw0_addr_in[9]
    DIRECTION INPUT ;
    USE SIGNAL ;
    SHAPE ABUTMENT ;
    PORT
      LAYER met3 ;
      RECT 1181.760 1391.130 1182.660 1391.430 ;
    END
  END rw0_addr_in[9]
  PIN r0_addr_in[0]
    DIRECTION INPUT ;
    USE SIGNAL ;
    SHAPE ABUTMENT ;
    PORT
      LAYER met3 ;
      RECT 0.000 1529.850 0.900 1530.150 ;
    END
  END r0_addr_in[0]
  PIN r0_addr_in[1]
    DIRECTION INPUT ;
    USE SIGNAL ;
    SHAPE ABUTMENT ;
    PORT
      LAYER met3 ;
      RECT 0.000 1599.210 0.900 1599.510 ;
    END
  END r0_addr_in[1]
  PIN r0_addr_in[2]
    DIRECTION INPUT ;
    USE SIGNAL ;
    SHAPE ABUTMENT ;
    PORT
      LAYER met3 ;
      RECT 0.000 1668.570 0.900 1668.870 ;
    END
  END r0_addr_in[2]
  PIN r0_addr_in[3]
    DIRECTION INPUT ;
    USE SIGNAL ;
    SHAPE ABUTMENT ;
    PORT
      LAYER met3 ;
      RECT 0.000 1737.930 0.900 1738.230 ;
    END
  END r0_addr_in[3]
  PIN r0_addr_in[4]
    DIRECTION INPUT ;
    USE SIGNAL ;
    SHAPE ABUTMENT ;
    PORT
      LAYER met3 ;
      RECT 0.000 1807.290 0.900 1807.590 ;
    END
  END r0_addr_in[4]
  PIN r0_addr_in[5]
    DIRECTION INPUT ;
    USE SIGNAL ;
    SHAPE ABUTMENT ;
    PORT
      LAYER met3 ;
      RECT 1181.760 1460.490 1182.660 1460.790 ;
    END
  END r0_addr_in[5]
  PIN r0_addr_in[6]
    DIRECTION INPUT ;
    USE SIGNAL ;
    SHAPE ABUTMENT ;
    PORT
      LAYER met3 ;
      RECT 1181.760 1529.850 1182.660 1530.150 ;
    END
  END r0_addr_in[6]
  PIN r0_addr_in[7]
    DIRECTION INPUT ;
    USE SIGNAL ;
    SHAPE ABUTMENT ;
    PORT
      LAYER met3 ;
      RECT 1181.760 1599.210 1182.660 1599.510 ;
    END
  END r0_addr_in[7]
  PIN r0_addr_in[8]
    DIRECTION INPUT ;
    USE SIGNAL ;
    SHAPE ABUTMENT ;
    PORT
      LAYER met3 ;
      RECT 1181.760 1668.570 1182.660 1668.870 ;
    END
  END r0_addr_in[8]
  PIN r0_addr_in[9]
    DIRECTION INPUT ;
    USE SIGNAL ;
    SHAPE ABUTMENT ;
    PORT
      LAYER met3 ;
      RECT 1181.760 1737.930 1182.660 1738.230 ;
    END
  END r0_addr_in[9]
  PIN rw0_we_in
    DIRECTION INPUT ;
    USE SIGNAL ;
    SHAPE ABUTMENT ;
    PORT
      LAYER met2 ;
      RECT 1062.530 1895.420 1062.670 1895.840 ;
    END
  END rw0_we_in
  PIN rw0_ce_in
    DIRECTION INPUT ;
    USE SIGNAL ;
    SHAPE ABUTMENT ;
    PORT
      LAYER met2 ;
      RECT 1079.090 1895.420 1079.230 1895.840 ;
    END
  END rw0_ce_in
  PIN rw0_clk
    DIRECTION INPUT ;
    USE SIGNAL ;
    SHAPE ABUTMENT ;
    PORT
      LAYER met2 ;
      RECT 1095.650 1895.420 1095.790 1895.840 ;
    END
  END rw0_clk
  PIN r0_ce_in
    DIRECTION INPUT ;
    USE SIGNAL ;
    SHAPE ABUTMENT ;
    PORT
      LAYER met2 ;
      RECT 1112.210 1895.420 1112.350 1895.840 ;
    END
  END r0_ce_in
  PIN r0_clk
    DIRECTION INPUT ;
    USE SIGNAL ;
    SHAPE ABUTMENT ;
    PORT
      LAYER met2 ;
      RECT 1128.770 1895.420 1128.910 1895.840 ;
    END
  END r0_clk
  PIN VSS
    DIRECTION INOUT ;
    USE GROUND ;
    PORT
      LAYER met4 ;
      RECT 2.160 4.080 3.360 1891.760 ;
      RECT 13.040 4.080 14.240 1891.760 ;
      RECT 23.920 4.080 25.120 1891.760 ;
      RECT 34.800 4.080 36.000 1891.760 ;
      RECT 45.680 4.080 46.880 1891.760 ;
      RECT 56.560 4.080 57.760 1891.760 ;
      RECT 67.440 4.080 68.640 1891.760 ;
      RECT 78.320 4.080 79.520 1891.760 ;
      RECT 89.200 4.080 90.400 1891.760 ;
      RECT 100.080 4.080 101.280 1891.760 ;
      RECT 110.960 4.080 112.160 1891.760 ;
      RECT 121.840 4.080 123.040 1891.760 ;
      RECT 132.720 4.080 133.920 1891.760 ;
      RECT 143.600 4.080 144.800 1891.760 ;
      RECT 154.480 4.080 155.680 1891.760 ;
      RECT 165.360 4.080 166.560 1891.760 ;
      RECT 176.240 4.080 177.440 1891.760 ;
      RECT 187.120 4.080 188.320 1891.760 ;
      RECT 198.000 4.080 199.200 1891.760 ;
      RECT 208.880 4.080 210.080 1891.760 ;
      RECT 219.760 4.080 220.960 1891.760 ;
      RECT 230.640 4.080 231.840 1891.760 ;
      RECT 241.520 4.080 242.720 1891.760 ;
      RECT 252.400 4.080 253.600 1891.760 ;
      RECT 263.280 4.080 264.480 1891.760 ;
      RECT 274.160 4.080 275.360 1891.760 ;
      RECT 285.040 4.080 286.240 1891.760 ;
      RECT 295.920 4.080 297.120 1891.760 ;
      RECT 306.800 4.080 308.000 1891.760 ;
      RECT 317.680 4.080 318.880 1891.760 ;
      RECT 328.560 4.080 329.760 1891.760 ;
      RECT 339.440 4.080 340.640 1891.760 ;
      RECT 350.320 4.080 351.520 1891.760 ;
      RECT 361.200 4.080 362.400 1891.760 ;
      RECT 372.080 4.080 373.280 1891.760 ;
      RECT 382.960 4.080 384.160 1891.760 ;
      RECT 393.840 4.080 395.040 1891.760 ;
      RECT 404.720 4.080 405.920 1891.760 ;
      RECT 415.600 4.080 416.800 1891.760 ;
      RECT 426.480 4.080 427.680 1891.760 ;
      RECT 437.360 4.080 438.560 1891.760 ;
      RECT 448.240 4.080 449.440 1891.760 ;
      RECT 459.120 4.080 460.320 1891.760 ;
      RECT 470.000 4.080 471.200 1891.760 ;
      RECT 480.880 4.080 482.080 1891.760 ;
      RECT 491.760 4.080 492.960 1891.760 ;
      RECT 502.640 4.080 503.840 1891.760 ;
      RECT 513.520 4.080 514.720 1891.760 ;
      RECT 524.400 4.080 525.600 1891.760 ;
      RECT 535.280 4.080 536.480 1891.760 ;
      RECT 546.160 4.080 547.360 1891.760 ;
      RECT 557.040 4.080 558.240 1891.760 ;
      RECT 567.920 4.080 569.120 1891.760 ;
      RECT 578.800 4.080 580.000 1891.760 ;
      RECT 589.680 4.080 590.880 1891.760 ;
      RECT 600.560 4.080 601.760 1891.760 ;
      RECT 611.440 4.080 612.640 1891.760 ;
      RECT 622.320 4.080 623.520 1891.760 ;
      RECT 633.200 4.080 634.400 1891.760 ;
      RECT 644.080 4.080 645.280 1891.760 ;
      RECT 654.960 4.080 656.160 1891.760 ;
      RECT 665.840 4.080 667.040 1891.760 ;
      RECT 676.720 4.080 677.920 1891.760 ;
      RECT 687.600 4.080 688.800 1891.760 ;
      RECT 698.480 4.080 699.680 1891.760 ;
      RECT 709.360 4.080 710.560 1891.760 ;
      RECT 720.240 4.080 721.440 1891.760 ;
      RECT 731.120 4.080 732.320 1891.760 ;
      RECT 742.000 4.080 743.200 1891.760 ;
      RECT 752.880 4.080 754.080 1891.760 ;
      RECT 763.760 4.080 764.960 1891.760 ;
      RECT 774.640 4.080 775.840 1891.760 ;
      RECT 785.520 4.080 786.720 1891.760 ;
      RECT 796.400 4.080 797.600 1891.760 ;
      RECT 807.280 4.080 808.480 1891.760 ;
      RECT 818.160 4.080 819.360 1891.760 ;
      RECT 829.040 4.080 830.240 1891.760 ;
      RECT 839.920 4.080 841.120 1891.760 ;
      RECT 850.800 4.080 852.000 1891.760 ;
      RECT 861.680 4.080 862.880 1891.760 ;
      RECT 872.560 4.080 873.760 1891.760 ;
      RECT 883.440 4.080 884.640 1891.760 ;
      RECT 894.320 4.080 895.520 1891.760 ;
      RECT 905.200 4.080 906.400 1891.760 ;
      RECT 916.080 4.080 917.280 1891.760 ;
      RECT 926.960 4.080 928.160 1891.760 ;
      RECT 937.840 4.080 939.040 1891.760 ;
      RECT 948.720 4.080 949.920 1891.760 ;
      RECT 959.600 4.080 960.800 1891.760 ;
      RECT 970.480 4.080 971.680 1891.760 ;
      RECT 981.360 4.080 982.560 1891.760 ;
      RECT 992.240 4.080 993.440 1891.760 ;
      RECT 1003.120 4.080 1004.320 1891.760 ;
      RECT 1014.000 4.080 1015.200 1891.760 ;
      RECT 1024.880 4.080 1026.080 1891.760 ;
      RECT 1035.760 4.080 1036.960 1891.760 ;
      RECT 1046.640 4.080 1047.840 1891.760 ;
      RECT 1057.520 4.080 1058.720 1891.760 ;
      RECT 1068.400 4.080 1069.600 1891.760 ;
      RECT 1079.280 4.080 1080.480 1891.760 ;
      RECT 1090.160 4.080 1091.360 1891.760 ;
      RECT 1101.040 4.080 1102.240 1891.760 ;
      RECT 1111.920 4.080 1113.120 1891.760 ;
      RECT 1122.800 4.080 1124.000 1891.760 ;
      RECT 1133.680 4.080 1134.880 1891.760 ;
      RECT 1144.560 4.080 1145.760 1891.760 ;
      RECT 1155.440 4.080 1156.640 1891.760 ;
      RECT 1166.320 4.080 1167.520 1891.760 ;
      RECT 1177.200 4.080 1178.400 1891.760 ;
    END
  END VSS
  PIN VDD
    DIRECTION INOUT ;
    USE POWER ;
    PORT
      LAYER met4 ;
      RECT 7.600 4.080 8.800 1891.760 ;
      RECT 18.480 4.080 19.680 1891.760 ;
      RECT 29.360 4.080 30.560 1891.760 ;
      RECT 40.240 4.080 41.440 1891.760 ;
      RECT 51.120 4.080 52.320 1891.760 ;
      RECT 62.000 4.080 63.200 1891.760 ;
      RECT 72.880 4.080 74.080 1891.760 ;
      RECT 83.760 4.080 84.960 1891.760 ;
      RECT 94.640 4.080 95.840 1891.760 ;
      RECT 105.520 4.080 106.720 1891.760 ;
      RECT 116.400 4.080 117.600 1891.760 ;
      RECT 127.280 4.080 128.480 1891.760 ;
      RECT 138.160 4.080 139.360 1891.760 ;
      RECT 149.040 4.080 150.240 1891.760 ;
      RECT 159.920 4.080 161.120 1891.760 ;
      RECT 170.800 4.080 172.000 1891.760 ;
      RECT 181.680 4.080 182.880 1891.760 ;
      RECT 192.560 4.080 193.760 1891.760 ;
      RECT 203.440 4.080 204.640 1891.760 ;
      RECT 214.320 4.080 215.520 1891.760 ;
      RECT 225.200 4.080 226.400 1891.760 ;
      RECT 236.080 4.080 237.280 1891.760 ;
      RECT 246.960 4.080 248.160 1891.760 ;
      RECT 257.840 4.080 259.040 1891.760 ;
      RECT 268.720 4.080 269.920 1891.760 ;
      RECT 279.600 4.080 280.800 1891.760 ;
      RECT 290.480 4.080 291.680 1891.760 ;
      RECT 301.360 4.080 302.560 1891.760 ;
      RECT 312.240 4.080 313.440 1891.760 ;
      RECT 323.120 4.080 324.320 1891.760 ;
      RECT 334.000 4.080 335.200 1891.760 ;
      RECT 344.880 4.080 346.080 1891.760 ;
      RECT 355.760 4.080 356.960 1891.760 ;
      RECT 366.640 4.080 367.840 1891.760 ;
      RECT 377.520 4.080 378.720 1891.760 ;
      RECT 388.400 4.080 389.600 1891.760 ;
      RECT 399.280 4.080 400.480 1891.760 ;
      RECT 410.160 4.080 411.360 1891.760 ;
      RECT 421.040 4.080 422.240 1891.760 ;
      RECT 431.920 4.080 433.120 1891.760 ;
      RECT 442.800 4.080 444.000 1891.760 ;
      RECT 453.680 4.080 454.880 1891.760 ;
      RECT 464.560 4.080 465.760 1891.760 ;
      RECT 475.440 4.080 476.640 1891.760 ;
      RECT 486.320 4.080 487.520 1891.760 ;
      RECT 497.200 4.080 498.400 1891.760 ;
      RECT 508.080 4.080 509.280 1891.760 ;
      RECT 518.960 4.080 520.160 1891.760 ;
      RECT 529.840 4.080 531.040 1891.760 ;
      RECT 540.720 4.080 541.920 1891.760 ;
      RECT 551.600 4.080 552.800 1891.760 ;
      RECT 562.480 4.080 563.680 1891.760 ;
      RECT 573.360 4.080 574.560 1891.760 ;
      RECT 584.240 4.080 585.440 1891.760 ;
      RECT 595.120 4.080 596.320 1891.760 ;
      RECT 606.000 4.080 607.200 1891.760 ;
      RECT 616.880 4.080 618.080 1891.760 ;
      RECT 627.760 4.080 628.960 1891.760 ;
      RECT 638.640 4.080 639.840 1891.760 ;
      RECT 649.520 4.080 650.720 1891.760 ;
      RECT 660.400 4.080 661.600 1891.760 ;
      RECT 671.280 4.080 672.480 1891.760 ;
      RECT 682.160 4.080 683.360 1891.760 ;
      RECT 693.040 4.080 694.240 1891.760 ;
      RECT 703.920 4.080 705.120 1891.760 ;
      RECT 714.800 4.080 716.000 1891.760 ;
      RECT 725.680 4.080 726.880 1891.760 ;
      RECT 736.560 4.080 737.760 1891.760 ;
      RECT 747.440 4.080 748.640 1891.760 ;
      RECT 758.320 4.080 759.520 1891.760 ;
      RECT 769.200 4.080 770.400 1891.760 ;
      RECT 780.080 4.080 781.280 1891.760 ;
      RECT 790.960 4.080 792.160 1891.760 ;
      RECT 801.840 4.080 803.040 1891.760 ;
      RECT 812.720 4.080 813.920 1891.760 ;
      RECT 823.600 4.080 824.800 1891.760 ;
      RECT 834.480 4.080 835.680 1891.760 ;
      RECT 845.360 4.080 846.560 1891.760 ;
      RECT 856.240 4.080 857.440 1891.760 ;
      RECT 867.120 4.080 868.320 1891.760 ;
      RECT 878.000 4.080 879.200 1891.760 ;
      RECT 888.880 4.080 890.080 1891.760 ;
      RECT 899.760 4.080 900.960 1891.760 ;
      RECT 910.640 4.080 911.840 1891.760 ;
      RECT 921.520 4.080 922.720 1891.760 ;
      RECT 932.400 4.080 933.600 1891.760 ;
      RECT 943.280 4.080 944.480 1891.760 ;
      RECT 954.160 4.080 955.360 1891.760 ;
      RECT 965.040 4.080 966.240 1891.760 ;
      RECT 975.920 4.080 977.120 1891.760 ;
      RECT 986.800 4.080 988.000 1891.760 ;
      RECT 997.680 4.080 998.880 1891.760 ;
      RECT 1008.560 4.080 1009.760 1891.760 ;
      RECT 1019.440 4.080 1020.640 1891.760 ;
      RECT 1030.320 4.080 1031.520 1891.760 ;
      RECT 1041.200 4.080 1042.400 1891.760 ;
      RECT 1052.080 4.080 1053.280 1891.760 ;
      RECT 1062.960 4.080 1064.160 1891.760 ;
      RECT 1073.840 4.080 1075.040 1891.760 ;
      RECT 1084.720 4.080 1085.920 1891.760 ;
      RECT 1095.600 4.080 1096.800 1891.760 ;
      RECT 1106.480 4.080 1107.680 1891.760 ;
      RECT 1117.360 4.080 1118.560 1891.760 ;
      RECT 1128.240 4.080 1129.440 1891.760 ;
      RECT 1139.120 4.080 1140.320 1891.760 ;
      RECT 1150.000 4.080 1151.200 1891.760 ;
      RECT 1160.880 4.080 1162.080 1891.760 ;
      RECT 1171.760 4.080 1172.960 1891.760 ;
    END
  END VDD
  OBS
    LAYER met1 ;
    RECT 0 0 1182.660 1895.840 ;
    LAYER met2 ;
    RECT 0 0 1182.660 1895.840 ;
    LAYER met3 ;
    RECT 0 0 1182.660 1895.840 ;
    LAYER met4 ;
    RECT 0 0 1182.660 1895.840 ;
  END
END fakeram_1rw1r_130w1024d_sram

END LIBRARY
